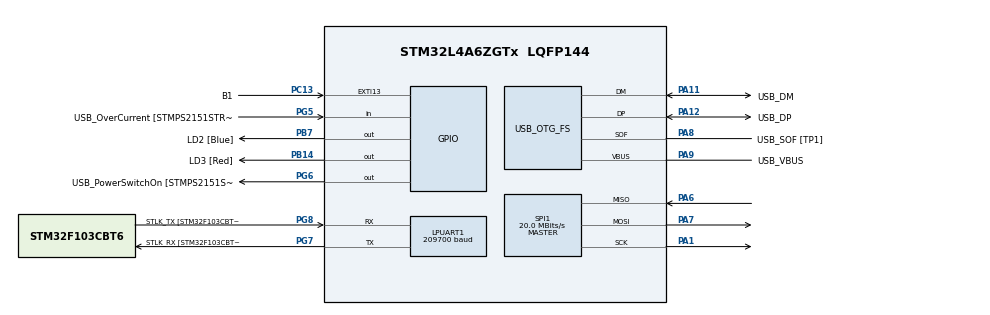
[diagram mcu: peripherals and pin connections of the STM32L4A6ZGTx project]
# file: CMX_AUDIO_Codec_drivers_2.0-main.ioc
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LPUART1.AutoBaudRateEnableParam=UART_ADVFEATURE_AUTOBAUDRATE_DISABLE
LPUART1.BaudRate=209700
LPUART1.DMADisableonRxErrorParam=UART_ADVFEATURE_DMA_ENABLEONRXERROR
LPUART1.DataInvertParam=UART_ADVFEATURE_DATAINV_DISABLE
LPUART1.MSBFirstParam=UART_ADVFEATURE_MSBFIRST_DISABLE
LPUART1.Mode=UART_MODE_TX_RX
LPUART1.OneBitSampling=UART_ONE_BIT_SAMPLE_DISABLE
LPUART1.OverrunDisableParam=UART_ADVFEATURE_OVERRUN_ENABLE
LPUART1.Parity=UART_PARITY_NONE
LPUART1.RxPinLevelInvertParam=UART_ADVFEATURE_RXINV_DISABLE
LPUART1.StopBits=UART_STOPBITS_1
LPUART1.SwapParam=UART_ADVFEATURE_SWAP_DISABLE
LPUART1.TxPinLevelInvertParam=UART_ADVFEATURE_TXINV_DISABLE
LPUART1.WordLength=UART_WORDLENGTH_7B
Mcu.Family=STM32L4
Mcu.Name=STM32L4A6ZGTx
Mcu.Package=LQFP144
NVIC.PriorityGroup=NVIC_PRIORITYGROUP_4
PA1.Mode=Full_Duplex_Master
PA1.Signal=SPI1_SCK
PA10.GPIO_Label=USB_ID
PA10.Signal=USB_OTG_FS_ID
PA11.GPIO_Label=USB_DM
PA11.Mode=Device_Only
PA11.Signal=USB_OTG_FS_DM
PA12.GPIO_Label=USB_DP
PA12.Mode=Device_Only
PA12.Signal=USB_OTG_FS_DP
PA13\ (JTMS/SWDIO).GPIO_Label=TMS
PA13\ (JTMS/SWDIO).Mode=Trace_Asynchronous_SW
PA13\ (JTMS/SWDIO).Signal=SYS_JTMS-SWDIO
PA14\ (JTCK/SWCLK).GPIO_Label=TCK
PA14\ (JTCK/SWCLK).Mode=Trace_Asynchronous_SW
PA14\ (JTCK/SWCLK).Signal=SYS_JTCK-SWCLK
PA6.Mode=Full_Duplex_Master
PA6.Signal=SPI1_MISO
PA7.Mode=Full_Duplex_Master
PA7.Signal=SPI1_MOSI
PA8.GPIO_Label=USB_SOF [TP1]
PA8.Mode=Activate_SOF_FS
PA8.Signal=USB_OTG_FS_SOF
PA9.GPIO_Label=USB_VBUS
PA9.Mode=Activate_VBUS
PA9.Signal=USB_OTG_FS_VBUS
PB14.GPIO_Label=LD3 [Red]
PB14.Signal=GPIO_Output
PB3\ (JTDO/TRACESWO).GPIO_Label=SWO
PB3\ (JTDO/TRACESWO).Mode=Trace_Asynchronous_SW
PB3\ (JTDO/TRACESWO).Signal=SYS_JTDO-SWO
PB7.GPIO_Label=LD2 [Blue]
PB7.Signal=GPIO_Output
PC13.GPIO_Label=B1
PC13.Signal=GPXTI13
PC14-OSC32_IN\ (PC14).Mode=LSE-External-Oscillator
PC14-OSC32_IN\ (PC14).Signal=RCC_OSC32_IN
PC15-OSC32_OUT\ (PC15).Mode=LSE-External-Oscillator
PC15-OSC32_OUT\ (PC15).Signal=RCC_OSC32_OUT
PG5.GPIO_Label=USB_OverCurrent [STMPS2151STR_FAULT]
PG5.Signal=GPIO_Input
PG6.GPIO_Label=USB_PowerSwitchOn [STMPS2151STR_EN]
PG6.Signal=GPIO_Output
PG7.GPIO_Label=STLK_RX [STM32F103CBT6_PA3]
PG7.Mode=Asynchronous
PG7.Signal=LPUART1_TX
PG8.GPIO_Label=STLK_TX [STM32F103CBT6_PA2]
PG8.Mode=Asynchronous
PG8.Signal=LPUART1_RX
PH1-OSC_OUT\ (PH1).Signal=RCC_OSC_OUT
ProjectManager.HeapSize=0x200
ProjectManager.StackSize=0x400
ProjectManager.TargetToolchain=STM32CubeIDE
RCC.ADCFreq_Value=48000000
RCC.AHBFreq_Value=80000000
RCC.APB1CLKDivider=RCC_HCLK_DIV4
RCC.APB1Freq_Value=20000000
RCC.APB1TimFreq_Value=40000000
RCC.APB2Freq_Value=80000000
RCC.APB2TimFreq_Value=80000000
RCC.CortexFreq_Value=80000000
RCC.FLatency=FLASH_LATENCY_4
RCC.HCLKFreq_Value=80000000
RCC.HSE_VALUE=8000000
RCC.HSI48_VALUE=48000000
RCC.HSI_VALUE=16000000
RCC.MSI_VALUE=4000000
RCC.PLLN=40
RCC.PLLSAI1N=24
RCC.SYSCLKFreq_VALUE=80000000
RCC.SYSCLKSource=RCC_SYSCLKSOURCE_PLLCLK
RCC.USBFreq_Value=48000000
RCC.VCOOutputFreq_Value=160000000
SPI1.BaudRatePrescaler=SPI_BAUDRATEPRESCALER_4
SPI1.CLKPhase=SPI_PHASE_2EDGE
SPI1.CLKPolarity=SPI_POLARITY_HIGH
SPI1.CalculateBaudRate=20.0 MBits/s
SPI1.DataSize=SPI_DATASIZE_8BIT
SPI1.Direction=SPI_DIRECTION_2LINES
SPI1.Mode=SPI_MODE_MASTER
SPI1.VirtualType=VM_MASTER
USB_OTG_FS.Sof_enable=ENABLE
USB_OTG_FS.VirtualMode=Device_Only
USB_OTG_FS.battery_charging_enable=ENABLE
USB_OTG_FS.low_power_enable=DISABLE
USB_OTG_FS.lpm_enable=DISABLE
USB_OTG_FS.use_dedicated_ep1=DISABLE
USB_OTG_FS.vbus_sensing_enable=ENABLE
board=NUCLEO-L4A6ZG

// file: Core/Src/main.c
/* USER CODE BEGIN Header */
/**
 ******************************************************************************
 * @file           : main.c
 * @brief          : Main program body
 ******************************************************************************
 * @attention
 *
 * Copyright (c) 2022 STMicroelectronics.
 * All rights reserved.
 *
 * This software is licensed under terms that can be found in the LICENSE file
 * in the root directory of this software component.
 * If no LICENSE file comes with this software, it is provided AS-IS.
 *
 ******************************************************************************
 */
/* USER CODE END Header */
#include "main.h"
#include "CODEC_REG.h"
#include "cbus.h"
#include "functional_image_alog.h"
#include "timer6_delay.h"
#include "unity.h"

/* USER CODE BEGIN PTD */
#define reset 0x01
#define SYNC_CTRL 0x04
#define AIG  0x05
#define AOG  0x06
#define VCFG 0x07
#define VCTRL 0x11
#define VCTR 0x3C
#define _1F   0x1F
#define _1D   0x1D
#define  _0A  0x0A
#define _09   0x09
#define enc 0x30
#define dec 0x10
#define status 0x40
/* USER CODE END PTD */

/* USER CODE BEGIN PD */
uint8_t arr[6];
uint8_t arr2[10];
//{ 0xAA, 0xbb, 0xff, 0xAe, 0xdd, 0xcc, 0xAb, 0xef, 0xcd, 0xbc };
//={ 0xAA,0xbb,0xff,0xee, 0xdd, 0xcc, 0xAb, 0xef,0xcd,0xbc };
uint16_t data;
/* USER CODE END PD */

UART_HandleTypeDef hlpuart1;

SPI_HandleTypeDef hspi1;

PCD_HandleTypeDef hpcd_USB_OTG_FS;

/* USER CODE BEGIN PV */
void sum(int a, int b){
	return a+b;
}

/* USER CODE END PV */

void SystemClock_Config(void);
static void MX_GPIO_Init(void);
static void MX_LPUART1_UART_Init(void);
static void MX_USB_OTG_FS_PCD_Init(void);
static void MX_SPI1_Init(void);
/* USER CODE BEGIN PFP */
void INPUT_CODEC_REG_SET();
void OUTPUT_CODEC_RED_SET();
/* USER CODE END PFP */

/* USER CODE BEGIN 0 */
uint16_t array[24];
static uint16_t x;
/* USER CODE END 0 */
//uint16_t *pointtoarray=array;

int main(void)
{
	/* USER CODE BEGIN 1 */
	//  char check[5];
	/* USER CODE END 1 */

	uint8_t address = 0xcd;
	uint16_t address_casted = (uint16_t)address;

	UNITY_BEGIN();
	/* MCU Configuration--------------------------------------------------------*/

	/* Reset of all peripherals, Initializes the Flash interface and the Systick. */
	HAL_Init();

	/* Configure the system clock */
	SystemClock_Config();

	/* Initialize all configured peripherals */
	MX_GPIO_Init();
	CBUS_INIT();
	MX_LPUART1_UART_Init();
	MX_USB_OTG_FS_PCD_Init();
	MX_SPI1_Init();
	/* USER CODE BEGIN 2 */

	//enable_codec_boot_control_gpios();
	//set_boot_en1_en2_high();
	enable_timer6();
	Cbus_Config(SPI3);
	CBUS_ENABLE(SPI3);

	CBUS_CHIP_SElECT_HIGH();

	HAL_Delay(30);

	CBUS_CHIP_SElECT_LOW();
	Cbus_Write_no_data(SPI3, reset);
	CBUS_CHIP_SElECT_HIGH();
//Delay_US(10000);
	HAL_Delay(100);

	CBUS_CHIP_SElECT_LOW();
	CbusWriteRegister(SPI3, _1F, 0xC107);
	CBUS_CHIP_SElECT_HIGH();
	HAL_Delay(100);

	CBUS_CHIP_SElECT_LOW();
	CbusWriteRegister(SPI3, _1D, 0x0006);
	CBUS_CHIP_SElECT_HIGH();
	HAL_Delay(100);

	CBUS_CHIP_SElECT_LOW();
//Cbus_Write_Byte(SPI3,_0A , 0x00);
	CbusWriteByte(SPI3, _0A, 0x00);
	CBUS_CHIP_SElECT_HIGH();
//Delay_US(100000);
	HAL_Delay(100);

	CBUS_CHIP_SElECT_LOW();
//Cbus_Write_Byte(SPI3,_09 , 0x0F);
	CbusWriteByte(SPI3, _09, 0x0F);
	CBUS_CHIP_SElECT_HIGH();
//Delay_US(100000);
	HAL_Delay(50);

	CBUS_CHIP_SElECT_LOW();
//Cbus_Write_Byte(SPI3,VCFG , 0x34);
	CbusWriteByte(SPI3, VCFG, 0x34);
	CBUS_CHIP_SElECT_HIGH();
//Delay_US(100000);
	HAL_Delay(100);

	CBUS_CHIP_SElECT_LOW();
//Cbus_Write_Byte(SPI3,AIG, 0x8F);
	CbusWriteByte(SPI3, AIG, 0x8F);
	CBUS_CHIP_SElECT_HIGH();
//Delay_US(100000);
	HAL_Delay(100);

	CBUS_CHIP_SElECT_LOW();
//Cbus_Write_Byte(SPI3,AOG , 0x0A);
	CbusWriteByte(SPI3, AOG, 0x05);
	CBUS_CHIP_SElECT_HIGH();
//Delay_US(100000);
	HAL_Delay(100);

	 CBUS_CHIP_SElECT_LOW();
	 CbusWriteRegister(SPI3, VCTRL, 0x0007);
	 CBUS_CHIP_SElECT_HIGH();
	 //Delay_US(100000);
	 HAL_Delay(80);

	 CBUS_CHIP_SElECT_LOW();
	  x = Cbus_Read_Word(SPI3, VCTR);
	 CBUS_CHIP_SElECT_HIGH();
	 HAL_Delay(80);

	while (1)

	{
		//Delay_US(80000);
		/*
		 CBUS_CHIP_SElECT_LOW();
		 //Cbus_Read_Byte_stream(SPI3,VCTR,arr,2);
		 uint16_t y = Cbus_Read_Word(SPI3, status);
		 CBUS_CHIP_SElECT_HIGH();
		 HAL_Delay(2);

		 while((y & 0x00C7) == 0x00C7){
		 Delay_US(80000);
		 CBUS_CHIP_SElECT_LOW();
		 Cbus_Read_Byte_stream(SPI3, enc, arr, 10);
		 CBUS_CHIP_SElECT_HIGH();
		 Delay_US(15);
		 CBUS_CHIP_SElECT_LOW();
		 Cbus_Write_Byte_stream(SPI3, 0x10, arr, 10);
		 CBUS_CHIP_SElECT_HIGH();

*/
		Delay_US(80000);

		CBUS_CHIP_SElECT_LOW();
		//Cbus_Read_Byte_stream(SPI3,VCTR,arr,2);
		uint16_t y = Cbus_Read_Word(SPI3, status);
		CBUS_CHIP_SElECT_HIGH();
		HAL_Delay(2);
		if((y & 0x0001) == 0x0001){

		  CBUS_CHIP_SElECT_LOW();
		  Cbus_Read_Byte_stream(SPI3, enc, arr, 6);
		  CBUS_CHIP_SElECT_HIGH();

		  CBUS_CHIP_SElECT_LOW();
		  Cbus_Write_Byte_stream(SPI3, 0x10, arr, 6);
		  CBUS_CHIP_SElECT_HIGH();

/*
		CBUS_CHIP_SElECT_LOW();
		CbusWriteRegister(SPI3, VCTRL, 0x1234);
		CBUS_CHIP_SElECT_HIGH();
		//Delay_US(100000);
		HAL_Delay(5);

		CBUS_CHIP_SElECT_LOW();
		//Cbus_Read_Byte_stream(SPI3,VCTR,arr,2);
		uint32_t x = Cbus_Read_Word(SPI3, VCTR);
		CBUS_CHIP_SElECT_HIGH();
		HAL_Delay(5);
*/
	}
}
}
void SystemClock_Config(void)
{
	RCC_OscInitTypeDef RCC_OscInitStruct =
	{ 0 };
	RCC_ClkInitTypeDef RCC_ClkInitStruct =
	{ 0 };

	/** Configure the main internal regulator output voltage
	 */
	if (HAL_PWREx_ControlVoltageScaling(PWR_REGULATOR_VOLTAGE_SCALE1) != HAL_OK)
	{
		Error_Handler();
	}

	/** Configure LSE Drive Capability
	 */
	HAL_PWR_EnableBkUpAccess();
	__HAL_RCC_LSEDRIVE_CONFIG(RCC_LSEDRIVE_LOW);

	/** Initializes the RCC Oscillators according to the specified parameters
	 * in the RCC_OscInitTypeDef structure.
	 */
	RCC_OscInitStruct.OscillatorType = RCC_OSCILLATORTYPE_LSE
			| RCC_OSCILLATORTYPE_MSI;
	RCC_OscInitStruct.LSEState = RCC_LSE_ON;
	RCC_OscInitStruct.MSIState = RCC_MSI_ON;
	RCC_OscInitStruct.MSICalibrationValue = 0;
	RCC_OscInitStruct.MSIClockRange = RCC_MSIRANGE_6;
	RCC_OscInitStruct.PLL.PLLState = RCC_PLL_ON;
	RCC_OscInitStruct.PLL.PLLSource = RCC_PLLSOURCE_MSI;
	RCC_OscInitStruct.PLL.PLLM = 1;
	RCC_OscInitStruct.PLL.PLLN = 40;
	RCC_OscInitStruct.PLL.PLLP = RCC_PLLP_DIV2;
	RCC_OscInitStruct.PLL.PLLQ = RCC_PLLQ_DIV2;
	RCC_OscInitStruct.PLL.PLLR = RCC_PLLR_DIV2;
	if (HAL_RCC_OscConfig(&RCC_OscInitStruct) != HAL_OK)
	{
		Error_Handler();
	}

	/** Initializes the CPU, AHB and APB buses clocks
	 */
	RCC_ClkInitStruct.ClockType = RCC_CLOCKTYPE_HCLK | RCC_CLOCKTYPE_SYSCLK
			| RCC_CLOCKTYPE_PCLK1 | RCC_CLOCKTYPE_PCLK2;
	RCC_ClkInitStruct.SYSCLKSource = RCC_SYSCLKSOURCE_PLLCLK;
	RCC_ClkInitStruct.AHBCLKDivider = RCC_SYSCLK_DIV1;
	RCC_ClkInitStruct.APB1CLKDivider = RCC_HCLK_DIV2;
	RCC_ClkInitStruct.APB2CLKDivider = RCC_HCLK_DIV1;

	if (HAL_RCC_ClockConfig(&RCC_ClkInitStruct, FLASH_LATENCY_4) != HAL_OK)
	{
		Error_Handler();
	}

	/** Enable MSI Auto calibration
	 */
	HAL_RCCEx_EnableMSIPLLMode();
}

static void MX_LPUART1_UART_Init(void)
{

	hlpuart1.Instance = LPUART1;
	hlpuart1.Init.BaudRate = 209700;
	hlpuart1.Init.WordLength = UART_WORDLENGTH_7B;
	hlpuart1.Init.StopBits = UART_STOPBITS_1;
	hlpuart1.Init.Parity = UART_PARITY_NONE;
	hlpuart1.Init.Mode = UART_MODE_TX_RX;
	hlpuart1.Init.HwFlowCtl = UART_HWCONTROL_NONE;
	hlpuart1.Init.OneBitSampling = UART_ONE_BIT_SAMPLE_DISABLE;
	hlpuart1.AdvancedInit.AdvFeatureInit = UART_ADVFEATURE_NO_INIT;
	if (HAL_UART_Init(&hlpuart1) != HAL_OK)
	{
		Error_Handler();
	}

}

static void MX_SPI1_Init(void)
{

	/* SPI1 parameter configuration*/
	hspi1.Instance = SPI1;
	hspi1.Init.Mode = SPI_MODE_MASTER;
	hspi1.Init.Direction = SPI_DIRECTION_2LINES;
	hspi1.Init.DataSize = SPI_DATASIZE_8BIT;
	hspi1.Init.CLKPolarity = SPI_POLARITY_HIGH;
	hspi1.Init.CLKPhase = SPI_PHASE_2EDGE;
	hspi1.Init.NSS = SPI_NSS_SOFT;
	hspi1.Init.BaudRatePrescaler = SPI_BAUDRATEPRESCALER_4;
	hspi1.Init.FirstBit = SPI_FIRSTBIT_MSB;
	hspi1.Init.TIMode = SPI_TIMODE_DISABLE;
	hspi1.Init.CRCCalculation = SPI_CRCCALCULATION_DISABLE;
	hspi1.Init.CRCPolynomial = 7;
	hspi1.Init.CRCLength = SPI_CRC_LENGTH_DATASIZE;
	hspi1.Init.NSSPMode = SPI_NSS_PULSE_DISABLE;
	if (HAL_SPI_Init(&hspi1) != HAL_OK)
	{
		Error_Handler();
	}

}

static void MX_USB_OTG_FS_PCD_Init(void)
{

	hpcd_USB_OTG_FS.Instance = USB_OTG_FS;
	hpcd_USB_OTG_FS.Init.dev_endpoints = 6;
	hpcd_USB_OTG_FS.Init.speed = PCD_SPEED_FULL;
	hpcd_USB_OTG_FS.Init.phy_itface = PCD_PHY_EMBEDDED;
	hpcd_USB_OTG_FS.Init.Sof_enable = ENABLE;
	hpcd_USB_OTG_FS.Init.low_power_enable = DISABLE;
	hpcd_USB_OTG_FS.Init.lpm_enable = DISABLE;
	hpcd_USB_OTG_FS.Init.battery_charging_enable = ENABLE;
	hpcd_USB_OTG_FS.Init.use_dedicated_ep1 = DISABLE;
	hpcd_USB_OTG_FS.Init.vbus_sensing_enable = ENABLE;
	if (HAL_PCD_Init(&hpcd_USB_OTG_FS) != HAL_OK)
	{
		Error_Handler();
	}

}

static void MX_GPIO_Init(void)
{
	GPIO_InitTypeDef GPIO_InitStruct =
	{ 0 };

	/* GPIO Ports Clock Enable */
	__HAL_RCC_GPIOC_CLK_ENABLE();
	__HAL_RCC_GPIOH_CLK_ENABLE();
	__HAL_RCC_GPIOA_CLK_ENABLE();
	__HAL_RCC_GPIOB_CLK_ENABLE();
	__HAL_RCC_GPIOG_CLK_ENABLE();
	HAL_PWREx_EnableVddIO2();

	/*Configure GPIO pin Output Level */
	HAL_GPIO_WritePin(GPIOB, LD3_Pin | LD2_Pin, GPIO_PIN_RESET);

	/*Configure GPIO pin Output Level */
	HAL_GPIO_WritePin(USB_PowerSwitchOn_GPIO_Port, USB_PowerSwitchOn_Pin,
			GPIO_PIN_RESET);

	/*Configure GPIO pin : B1_Pin */
	GPIO_InitStruct.Pin = B1_Pin;
	GPIO_InitStruct.Mode = GPIO_MODE_IT_RISING;
	GPIO_InitStruct.Pull = GPIO_NOPULL;
	HAL_GPIO_Init(B1_GPIO_Port, &GPIO_InitStruct);

	/*Configure GPIO pins : LD3_Pin LD2_Pin */
	GPIO_InitStruct.Pin = LD3_Pin | LD2_Pin;
	GPIO_InitStruct.Mode = GPIO_MODE_OUTPUT_PP;
	GPIO_InitStruct.Pull = GPIO_NOPULL;
	GPIO_InitStruct.Speed = GPIO_SPEED_FREQ_LOW;
	HAL_GPIO_Init(GPIOB, &GPIO_InitStruct);

	/*Configure GPIO pin : USB_OverCurrent_Pin */
	GPIO_InitStruct.Pin = USB_OverCurrent_Pin;
	GPIO_InitStruct.Mode = GPIO_MODE_INPUT;
	GPIO_InitStruct.Pull = GPIO_NOPULL;
	HAL_GPIO_Init(USB_OverCurrent_GPIO_Port, &GPIO_InitStruct);

	/*Configure GPIO pin : USB_PowerSwitchOn_Pin */
	GPIO_InitStruct.Pin = USB_PowerSwitchOn_Pin;
	GPIO_InitStruct.Mode = GPIO_MODE_OUTPUT_PP;
	GPIO_InitStruct.Pull = GPIO_NOPULL;
	GPIO_InitStruct.Speed = GPIO_SPEED_FREQ_LOW;
	HAL_GPIO_Init(USB_PowerSwitchOn_GPIO_Port, &GPIO_InitStruct);

}

/* USER CODE BEGIN 4 */
void CODEC1_REG_SET()
{
	HAL_Delay(100);
	CBUS_CHIP_SElECT_LOW();
	CbusWriteRegister(SPI3, MODE, 0x0210); //0024
	CBUS_CHIP_SElECT_HIGH();
	HAL_Delay(50);

	CBUS_CHIP_SElECT_LOW();
	CbusWriteRegister(SPI3, Input_type, 0x0124); //0024
	CBUS_CHIP_SElECT_HIGH();
	HAL_Delay(50);

	CBUS_CHIP_SElECT_LOW();
	CbusWriteRegister(SPI3, Output_type, 0x0124); //0024
	CBUS_CHIP_SElECT_HIGH();
	HAL_Delay(50);

	CBUS_CHIP_SElECT_LOW();
	CbusWriteRegister(SPI3, MODE, 0x0212); //0222
	CBUS_CHIP_SElECT_HIGH();
	HAL_Delay(50);

	CBUS_CHIP_SElECT_LOW();
	CbusWriteRegister(SPI3, ANAIN_Coarse_GAIN, 0x0500); //0A66
	CBUS_CHIP_SElECT_HIGH();
	HAL_Delay(50);

	CBUS_CHIP_SElECT_LOW();
	CbusWriteRegister(SPI3, ANAIN_Config, 0x0A09); //0A66
	CBUS_CHIP_SElECT_HIGH();
	HAL_Delay(50);

	CBUS_CHIP_SElECT_LOW();
	CbusWriteRegister(SPI3, Fine_Gain_Channel_1, 0x0080); //0A66
	CBUS_CHIP_SElECT_HIGH();
	HAL_Delay(50);
}

void OUTPUT_CODEC_RED_SET()
{

	CBUS_CHIP_SElECT_OUPUT_CODEC_LOW();
	CbusWriteRegister(SPI3, MODE, 0x0120);
	CBUS_CHIP_SElECT_OUPUT_CODEC_HIGH();
	HAL_Delay(50);

	CBUS_CHIP_SElECT_OUPUT_CODEC_LOW();
	CbusWriteRegister(SPI3, Input_type, 0x0124);
	CBUS_CHIP_SElECT_OUPUT_CODEC_HIGH();
	HAL_Delay(50);

	CBUS_CHIP_SElECT_OUPUT_CODEC_LOW();
	CbusWriteRegister(SPI3, Output_type, 0x0124);
	CBUS_CHIP_SElECT_OUPUT_CODEC_HIGH();
	HAL_Delay(50);

	CBUS_CHIP_SElECT_OUPUT_CODEC_LOW();
	CbusWriteRegister(SPI3, MODE, 0x0122);
	CBUS_CHIP_SElECT_OUPUT_CODEC_HIGH();
	HAL_Delay(50);

	CBUS_CHIP_SElECT_OUPUT_CODEC_LOW();
	CbusWriteRegister(SPI3, ANAOUT_CONFIG, 0x0A66);
	CBUS_CHIP_SElECT_OUPUT_CODEC_HIGH();
	HAL_Delay(50);

	CBUS_CHIP_SElECT_OUPUT_CODEC_LOW();
	CbusWriteRegister(SPI3, SPKR_COARSE_GAIN, 0x8000);
	CBUS_CHIP_SElECT_OUPUT_CODEC_HIGH();
	HAL_Delay(50);

	CBUS_CHIP_SElECT_OUPUT_CODEC_LOW();
	CbusWriteRegister(SPI3, Fine_Gain_Channel_1, 0x0090);
	CBUS_CHIP_SElECT_OUPUT_CODEC_HIGH();
	HAL_Delay(50);

}
/* USER CODE END 4 */

void Error_Handler(void)
{
	__disable_irq();
	while (1)
	{
	}
}
